One B-rep face of a CAD part: STEP entity #770172.
In plain terms, the planar face has unit normal (0, 0, -1).
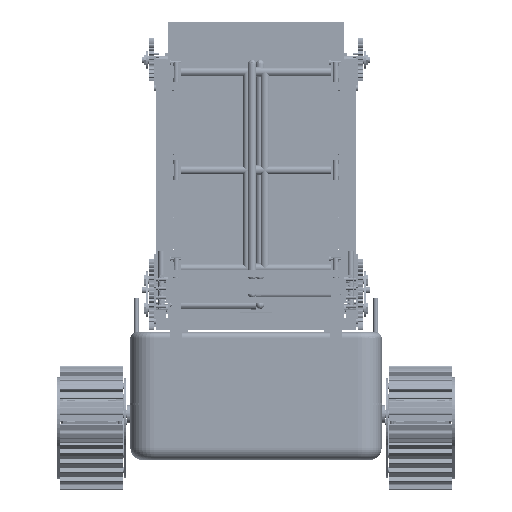
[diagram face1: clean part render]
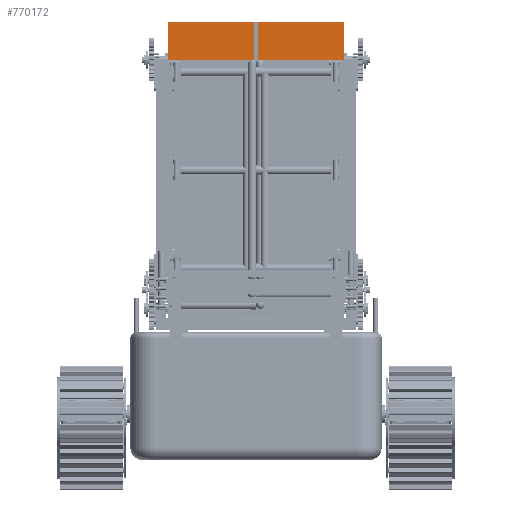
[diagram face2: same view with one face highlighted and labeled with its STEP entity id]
Length unit declared in the file: centimetre
Its self-contained STEP definition (entity closure, numbers rounded to 3 decimals, lengths and spline knots to 4 decimals):
#769863 = VERTEX_POINT('',#769864);
#769864 = CARTESIAN_POINT('',(-19.,-44.,9.2));
#769873 = PLANE('',#769874);
#769874 = AXIS2_PLACEMENT_3D('',#769875,#769876,#769877);
#769875 = CARTESIAN_POINT('',(-19.,-44.,9.2));
#769876 = DIRECTION('',(1.,0.,0.));
#769877 = DIRECTION('',(0.,0.,1.));
#769885 = PLANE('',#769886);
#769886 = AXIS2_PLACEMENT_3D('',#769887,#769888,#769889);
#769887 = CARTESIAN_POINT('',(-19.,-44.,9.2));
#769888 = DIRECTION('',(0.,1.,0.));
#769889 = DIRECTION('',(0.,0.,1.));
#769897 = EDGE_CURVE('',#769863,#769898,#769900,.T.);
#769898 = VERTEX_POINT('',#769899);
#769899 = CARTESIAN_POINT('',(-19.,44.,9.2));
#769900 = SURFACE_CURVE('',#769901,(#769905,#769912),.PCURVE_S1.);
#769901 = LINE('',#769902,#769903);
#769902 = CARTESIAN_POINT('',(-19.,-44.,9.2));
#769903 = VECTOR('',#769904,0.1);
#769904 = DIRECTION('',(0.,1.,0.));
#769905 = PCURVE('',#769873,#769906);
#769906 = DEFINITIONAL_REPRESENTATION('',(#769907),#769911);
#769907 = LINE('',#769908,#769909);
#769908 = CARTESIAN_POINT('',(0.,0.));
#769909 = VECTOR('',#769910,1.);
#769910 = DIRECTION('',(0.,-1.));
#769911 = ( GEOMETRIC_REPRESENTATION_CONTEXT(2) 
PARAMETRIC_REPRESENTATION_CONTEXT() REPRESENTATION_CONTEXT('2D SPACE',''
  ) );
#769912 = PCURVE('',#769913,#769918);
#769913 = PLANE('',#769914);
#769914 = AXIS2_PLACEMENT_3D('',#769915,#769916,#769917);
#769915 = CARTESIAN_POINT('',(-19.,-44.,9.2));
#769916 = DIRECTION('',(0.,0.,1.));
#769917 = DIRECTION('',(1.,0.,0.));
#769918 = DEFINITIONAL_REPRESENTATION('',(#769919),#769923);
#769919 = LINE('',#769920,#769921);
#769920 = CARTESIAN_POINT('',(0.,0.));
#769921 = VECTOR('',#769922,1.);
#769922 = DIRECTION('',(0.,1.));
#769923 = ( GEOMETRIC_REPRESENTATION_CONTEXT(2) 
PARAMETRIC_REPRESENTATION_CONTEXT() REPRESENTATION_CONTEXT('2D SPACE',''
  ) );
#769941 = PLANE('',#769942);
#769942 = AXIS2_PLACEMENT_3D('',#769943,#769944,#769945);
#769943 = CARTESIAN_POINT('',(-19.,44.,9.2));
#769944 = DIRECTION('',(0.,1.,0.));
#769945 = DIRECTION('',(0.,0.,1.));
#769983 = VERTEX_POINT('',#769984);
#769984 = CARTESIAN_POINT('',(0.,-44.,9.2));
#769993 = PLANE('',#769994);
#769994 = AXIS2_PLACEMENT_3D('',#769995,#769996,#769997);
#769995 = CARTESIAN_POINT('',(0.,-44.,9.2));
#769996 = DIRECTION('',(1.,0.,0.));
#769997 = DIRECTION('',(0.,0.,1.));
#770012 = EDGE_CURVE('',#769983,#770013,#770015,.T.);
#770013 = VERTEX_POINT('',#770014);
#770014 = CARTESIAN_POINT('',(0.,44.,9.2));
#770015 = SURFACE_CURVE('',#770016,(#770020,#770027),.PCURVE_S1.);
#770016 = LINE('',#770017,#770018);
#770017 = CARTESIAN_POINT('',(0.,-44.,9.2));
#770018 = VECTOR('',#770019,0.1);
#770019 = DIRECTION('',(0.,1.,0.));
#770020 = PCURVE('',#769993,#770021);
#770021 = DEFINITIONAL_REPRESENTATION('',(#770022),#770026);
#770022 = LINE('',#770023,#770024);
#770023 = CARTESIAN_POINT('',(0.,0.));
#770024 = VECTOR('',#770025,1.);
#770025 = DIRECTION('',(0.,-1.));
#770026 = ( GEOMETRIC_REPRESENTATION_CONTEXT(2) 
PARAMETRIC_REPRESENTATION_CONTEXT() REPRESENTATION_CONTEXT('2D SPACE',''
  ) );
#770027 = PCURVE('',#769913,#770028);
#770028 = DEFINITIONAL_REPRESENTATION('',(#770029),#770033);
#770029 = LINE('',#770030,#770031);
#770030 = CARTESIAN_POINT('',(19.,0.));
#770031 = VECTOR('',#770032,1.);
#770032 = DIRECTION('',(0.,1.));
#770033 = ( GEOMETRIC_REPRESENTATION_CONTEXT(2) 
PARAMETRIC_REPRESENTATION_CONTEXT() REPRESENTATION_CONTEXT('2D SPACE',''
  ) );
#770082 = EDGE_CURVE('',#769863,#769983,#770083,.T.);
#770083 = SURFACE_CURVE('',#770084,(#770088,#770095),.PCURVE_S1.);
#770084 = LINE('',#770085,#770086);
#770085 = CARTESIAN_POINT('',(-19.,-44.,9.2));
#770086 = VECTOR('',#770087,0.1);
#770087 = DIRECTION('',(1.,0.,0.));
#770088 = PCURVE('',#769885,#770089);
#770089 = DEFINITIONAL_REPRESENTATION('',(#770090),#770094);
#770090 = LINE('',#770091,#770092);
#770091 = CARTESIAN_POINT('',(0.,0.));
#770092 = VECTOR('',#770093,1.);
#770093 = DIRECTION('',(0.,1.));
#770094 = ( GEOMETRIC_REPRESENTATION_CONTEXT(2) 
PARAMETRIC_REPRESENTATION_CONTEXT() REPRESENTATION_CONTEXT('2D SPACE',''
  ) );
#770095 = PCURVE('',#769913,#770096);
#770096 = DEFINITIONAL_REPRESENTATION('',(#770097),#770101);
#770097 = LINE('',#770098,#770099);
#770098 = CARTESIAN_POINT('',(0.,0.));
#770099 = VECTOR('',#770100,1.);
#770100 = DIRECTION('',(1.,0.));
#770101 = ( GEOMETRIC_REPRESENTATION_CONTEXT(2) 
PARAMETRIC_REPRESENTATION_CONTEXT() REPRESENTATION_CONTEXT('2D SPACE',''
  ) );
#770129 = EDGE_CURVE('',#769898,#770013,#770130,.T.);
#770130 = SURFACE_CURVE('',#770131,(#770135,#770142),.PCURVE_S1.);
#770131 = LINE('',#770132,#770133);
#770132 = CARTESIAN_POINT('',(-19.,44.,9.2));
#770133 = VECTOR('',#770134,0.1);
#770134 = DIRECTION('',(1.,0.,0.));
#770135 = PCURVE('',#769941,#770136);
#770136 = DEFINITIONAL_REPRESENTATION('',(#770137),#770141);
#770137 = LINE('',#770138,#770139);
#770138 = CARTESIAN_POINT('',(0.,0.));
#770139 = VECTOR('',#770140,1.);
#770140 = DIRECTION('',(0.,1.));
#770141 = ( GEOMETRIC_REPRESENTATION_CONTEXT(2) 
PARAMETRIC_REPRESENTATION_CONTEXT() REPRESENTATION_CONTEXT('2D SPACE',''
  ) );
#770142 = PCURVE('',#769913,#770143);
#770143 = DEFINITIONAL_REPRESENTATION('',(#770144),#770148);
#770144 = LINE('',#770145,#770146);
#770145 = CARTESIAN_POINT('',(0.,88.));
#770146 = VECTOR('',#770147,1.);
#770147 = DIRECTION('',(1.,0.));
#770148 = ( GEOMETRIC_REPRESENTATION_CONTEXT(2) 
PARAMETRIC_REPRESENTATION_CONTEXT() REPRESENTATION_CONTEXT('2D SPACE',''
  ) );
#770172 = ADVANCED_FACE('',(#770173),#769913,.F.);
#770173 = FACE_BOUND('',#770174,.F.);
#770174 = EDGE_LOOP('',(#770175,#770176,#770177,#770178));
#770175 = ORIENTED_EDGE('',*,*,#769897,.F.);
#770176 = ORIENTED_EDGE('',*,*,#770082,.T.);
#770177 = ORIENTED_EDGE('',*,*,#770012,.T.);
#770178 = ORIENTED_EDGE('',*,*,#770129,.F.);
